One B-rep face of a CAD part: STEP entity #338.
In plain terms, the planar face has unit normal (0, 0, 1).
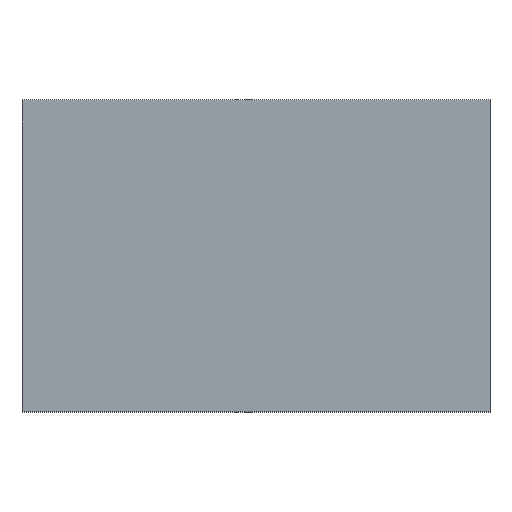
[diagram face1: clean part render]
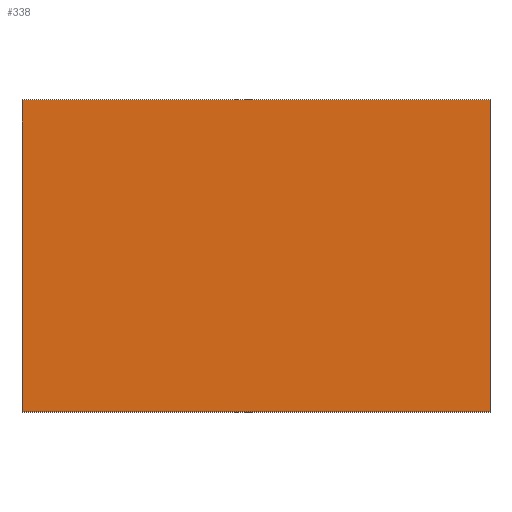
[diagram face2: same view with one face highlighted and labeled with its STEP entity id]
Its self-contained STEP definition (entity closure, numbers rounded to 3 decimals):
#24 = VERTEX_POINT('',#25);
#25 = CARTESIAN_POINT('',(84.,61.,200.));
#32 = PLANE('',#33);
#33 = AXIS2_PLACEMENT_3D('',#34,#35,#36);
#34 = CARTESIAN_POINT('',(84.,61.,198.));
#35 = DIRECTION('',(1.,0.,0.));
#36 = DIRECTION('',(0.,0.,1.));
#44 = PLANE('',#45);
#45 = AXIS2_PLACEMENT_3D('',#46,#47,#48);
#46 = CARTESIAN_POINT('',(84.,61.,198.));
#47 = DIRECTION('',(0.,1.,0.));
#48 = DIRECTION('',(0.,0.,1.));
#85 = VERTEX_POINT('',#86);
#86 = CARTESIAN_POINT('',(84.,69.,200.));
#100 = PLANE('',#101);
#101 = AXIS2_PLACEMENT_3D('',#102,#103,#104);
#102 = CARTESIAN_POINT('',(84.,69.,198.));
#103 = DIRECTION('',(0.,1.,0.));
#104 = DIRECTION('',(0.,0.,1.));
#112 = EDGE_CURVE('',#24,#85,#113,.T.);
#113 = SURFACE_CURVE('',#114,(#118,#125),.PCURVE_S1.);
#114 = LINE('',#115,#116);
#115 = CARTESIAN_POINT('',(84.,61.,200.));
#116 = VECTOR('',#117,1.);
#117 = DIRECTION('',(0.,1.,0.));
#118 = PCURVE('',#32,#119);
#119 = DEFINITIONAL_REPRESENTATION('',(#120),#124);
#120 = LINE('',#121,#122);
#121 = CARTESIAN_POINT('',(2.,0.));
#122 = VECTOR('',#123,1.);
#123 = DIRECTION('',(0.,-1.));
#124 = ( GEOMETRIC_REPRESENTATION_CONTEXT(2) 
PARAMETRIC_REPRESENTATION_CONTEXT() REPRESENTATION_CONTEXT('2D SPACE',''
  ) );
#125 = PCURVE('',#126,#131);
#126 = PLANE('',#127);
#127 = AXIS2_PLACEMENT_3D('',#128,#129,#130);
#128 = CARTESIAN_POINT('',(84.,61.,200.));
#129 = DIRECTION('',(0.,0.,1.));
#130 = DIRECTION('',(1.,0.,0.));
#131 = DEFINITIONAL_REPRESENTATION('',(#132),#136);
#132 = LINE('',#133,#134);
#133 = CARTESIAN_POINT('',(0.,0.));
#134 = VECTOR('',#135,1.);
#135 = DIRECTION('',(0.,1.));
#136 = ( GEOMETRIC_REPRESENTATION_CONTEXT(2) 
PARAMETRIC_REPRESENTATION_CONTEXT() REPRESENTATION_CONTEXT('2D SPACE',''
  ) );
#144 = VERTEX_POINT('',#145);
#145 = CARTESIAN_POINT('',(96.,61.,200.));
#152 = PLANE('',#153);
#153 = AXIS2_PLACEMENT_3D('',#154,#155,#156);
#154 = CARTESIAN_POINT('',(96.,61.,198.));
#155 = DIRECTION('',(1.,0.,0.));
#156 = DIRECTION('',(0.,0.,1.));
#195 = VERTEX_POINT('',#196);
#196 = CARTESIAN_POINT('',(96.,69.,200.));
#217 = EDGE_CURVE('',#144,#195,#218,.T.);
#218 = SURFACE_CURVE('',#219,(#223,#230),.PCURVE_S1.);
#219 = LINE('',#220,#221);
#220 = CARTESIAN_POINT('',(96.,61.,200.));
#221 = VECTOR('',#222,1.);
#222 = DIRECTION('',(0.,1.,0.));
#223 = PCURVE('',#152,#224);
#224 = DEFINITIONAL_REPRESENTATION('',(#225),#229);
#225 = LINE('',#226,#227);
#226 = CARTESIAN_POINT('',(2.,0.));
#227 = VECTOR('',#228,1.);
#228 = DIRECTION('',(0.,-1.));
#229 = ( GEOMETRIC_REPRESENTATION_CONTEXT(2) 
PARAMETRIC_REPRESENTATION_CONTEXT() REPRESENTATION_CONTEXT('2D SPACE',''
  ) );
#230 = PCURVE('',#126,#231);
#231 = DEFINITIONAL_REPRESENTATION('',(#232),#236);
#232 = LINE('',#233,#234);
#233 = CARTESIAN_POINT('',(12.,0.));
#234 = VECTOR('',#235,1.);
#235 = DIRECTION('',(0.,1.));
#236 = ( GEOMETRIC_REPRESENTATION_CONTEXT(2) 
PARAMETRIC_REPRESENTATION_CONTEXT() REPRESENTATION_CONTEXT('2D SPACE',''
  ) );
#263 = EDGE_CURVE('',#24,#144,#264,.T.);
#264 = SURFACE_CURVE('',#265,(#269,#276),.PCURVE_S1.);
#265 = LINE('',#266,#267);
#266 = CARTESIAN_POINT('',(84.,61.,200.));
#267 = VECTOR('',#268,1.);
#268 = DIRECTION('',(1.,0.,0.));
#269 = PCURVE('',#44,#270);
#270 = DEFINITIONAL_REPRESENTATION('',(#271),#275);
#271 = LINE('',#272,#273);
#272 = CARTESIAN_POINT('',(2.,0.));
#273 = VECTOR('',#274,1.);
#274 = DIRECTION('',(0.,1.));
#275 = ( GEOMETRIC_REPRESENTATION_CONTEXT(2) 
PARAMETRIC_REPRESENTATION_CONTEXT() REPRESENTATION_CONTEXT('2D SPACE',''
  ) );
#276 = PCURVE('',#126,#277);
#277 = DEFINITIONAL_REPRESENTATION('',(#278),#282);
#278 = LINE('',#279,#280);
#279 = CARTESIAN_POINT('',(0.,0.));
#280 = VECTOR('',#281,1.);
#281 = DIRECTION('',(1.,0.));
#282 = ( GEOMETRIC_REPRESENTATION_CONTEXT(2) 
PARAMETRIC_REPRESENTATION_CONTEXT() REPRESENTATION_CONTEXT('2D SPACE',''
  ) );
#310 = EDGE_CURVE('',#85,#195,#311,.T.);
#311 = SURFACE_CURVE('',#312,(#316,#323),.PCURVE_S1.);
#312 = LINE('',#313,#314);
#313 = CARTESIAN_POINT('',(84.,69.,200.));
#314 = VECTOR('',#315,1.);
#315 = DIRECTION('',(1.,0.,0.));
#316 = PCURVE('',#100,#317);
#317 = DEFINITIONAL_REPRESENTATION('',(#318),#322);
#318 = LINE('',#319,#320);
#319 = CARTESIAN_POINT('',(2.,0.));
#320 = VECTOR('',#321,1.);
#321 = DIRECTION('',(0.,1.));
#322 = ( GEOMETRIC_REPRESENTATION_CONTEXT(2) 
PARAMETRIC_REPRESENTATION_CONTEXT() REPRESENTATION_CONTEXT('2D SPACE',''
  ) );
#323 = PCURVE('',#126,#324);
#324 = DEFINITIONAL_REPRESENTATION('',(#325),#329);
#325 = LINE('',#326,#327);
#326 = CARTESIAN_POINT('',(0.,8.));
#327 = VECTOR('',#328,1.);
#328 = DIRECTION('',(1.,0.));
#329 = ( GEOMETRIC_REPRESENTATION_CONTEXT(2) 
PARAMETRIC_REPRESENTATION_CONTEXT() REPRESENTATION_CONTEXT('2D SPACE',''
  ) );
#338 = ADVANCED_FACE('',(#339),#126,.T.);
#339 = FACE_BOUND('',#340,.T.);
#340 = EDGE_LOOP('',(#341,#342,#343,#344));
#341 = ORIENTED_EDGE('',*,*,#112,.F.);
#342 = ORIENTED_EDGE('',*,*,#263,.T.);
#343 = ORIENTED_EDGE('',*,*,#217,.T.);
#344 = ORIENTED_EDGE('',*,*,#310,.F.);
